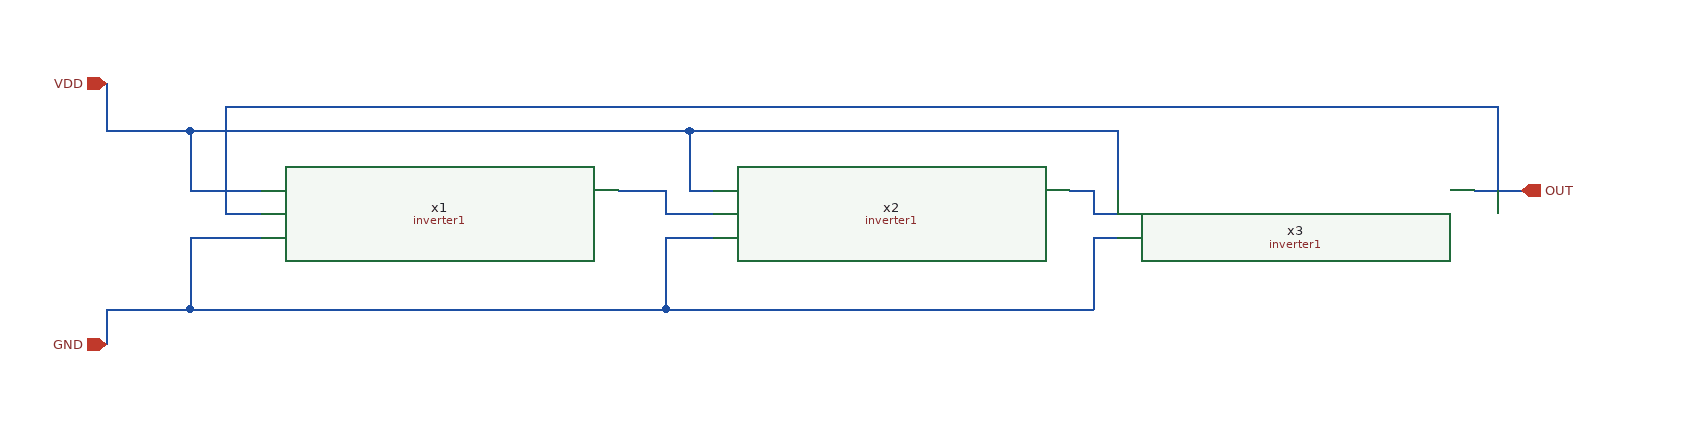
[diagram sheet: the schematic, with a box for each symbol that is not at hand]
v {xschem version=3.4.6RC file_version=1.2
}
G {}
K {}
V {}
S {}
E {}
N 520 -20 540 -20 {lab=#net1}
N 540 -20 540 -0 {lab=#net1}
N 540 -0 560 -0 {lab=#net1}
N 140 -20 170 -20 {lab=#net2}
N 170 -20 180 -20 {lab=#net2}
N 180 -20 180 0 {lab=#net2}
N 180 0 220 0 {lab=#net2}
N 860 -20 900 -20 {lab=OUT}
N -220 20 -160 20 {lab=GND}
N -220 20 -220 80 {lab=GND}
N -290 80 -220 80 {lab=GND}
N 180 20 220 20 {lab=GND}
N 180 20 180 80 {lab=GND}
N -220 80 180 80 {lab=GND}
N 540 20 560 20 {lab=GND}
N 540 20 540 80 {lab=GND}
N 180 80 540 80 {lab=GND}
N -220 -20 -160 -20 {lab=VDD}
N -220 -70 -220 -20 {lab=VDD}
N -290 -70 -220 -70 {lab=VDD}
N 200 -20 220 -20 {lab=VDD}
N 200 -70 200 -20 {lab=VDD}
N -220 -70 200 -70 {lab=VDD}
N 560 -70 560 -20 {lab=VDD}
N 200 -70 560 -70 {lab=VDD}
N 880 -90 880 -20 {lab=OUT}
N -190 -90 880 -90 {lab=OUT}
N -190 -90 -190 -0 {lab=OUT}
N -190 -0 -160 -0 {lab=OUT}
N -290 -110 -290 -70 {lab=VDD}
N -290 80 -290 110 {lab=GND}
C {devices/opin.sym} 900 -20 0 0 {name=p1 lab=OUT}
C {devices/iopin.sym} -290 -110 0 0 {name=p2 lab=VDD}
C {devices/iopin.sym} -290 110 0 0 {name=p5 lab=GND}
C {/home/ardian/Design/inverter/inverter1.sym} -10 0 0 0 {name=x1}
C {/home/ardian/Design/inverter/inverter1.sym} 370 0 0 0 {name=x2}
C {/home/ardian/Design/inverter/inverter1.sym} 710 0 0 0 {name=x3}
